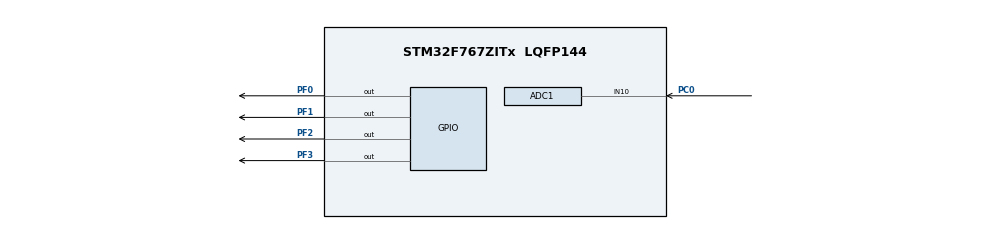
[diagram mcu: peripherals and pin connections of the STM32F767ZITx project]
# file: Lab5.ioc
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ADC1.Channel-0\#ChannelRegularConversion=ADC_CHANNEL_10
ADC1.ContinuousConvMode=ENABLE
ADC1.EOCSelection=ADC_EOC_SEQ_CONV
ADC1.NbrOfConversionFlag=1
ADC1.Rank-0\#ChannelRegularConversion=1
ADC1.SamplingTime-0\#ChannelRegularConversion=ADC_SAMPLETIME_3CYCLES
ADC1.master=1
CORTEX_M7.default_mode_Activation=1
Mcu.Family=STM32F7
Mcu.Name=STM32F767ZITx
Mcu.Package=LQFP144
NVIC.PriorityGroup=NVIC_PRIORITYGROUP_4
PC0.Signal=ADCx_IN10
PF0.Signal=GPIO_Output
PF1.Signal=GPIO_Output
PF2.Signal=GPIO_Output
PF3.Signal=GPIO_Output
ProjectManager.HeapSize=0x200
ProjectManager.StackSize=0x400
ProjectManager.TargetToolchain=STM32CubeIDE
RCC.AHBFreq_Value=216000000
RCC.APB1CLKDivider=RCC_HCLK_DIV4
RCC.APB1Freq_Value=54000000
RCC.APB1TimFreq_Value=108000000
RCC.APB2CLKDivider=RCC_HCLK_DIV2
RCC.APB2Freq_Value=108000000
RCC.APB2TimFreq_Value=216000000
RCC.CortexFreq_Value=216000000
RCC.HCLKFreq_Value=216000000
RCC.HSE_VALUE=25000000
RCC.HSI_VALUE=16000000
RCC.LSE_VALUE=32768
RCC.PLLM=8
RCC.PLLN=216
RCC.SYSCLKFreq_VALUE=216000000
RCC.SYSCLKSource=RCC_SYSCLKSOURCE_PLLCLK
RCC.USBFreq_Value=216000000
RCC.VCOOutputFreq_Value=432000000
SH.ADCx_IN10.0=ADC1_IN10,IN10
board=custom

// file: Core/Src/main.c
/* USER CODE BEGIN Header */
/**
  ******************************************************************************
  * @file           : main.c
  * @brief          : Main program body
  ******************************************************************************
  * @attention
  *
  * Copyright (c) 2026 STMicroelectronics.
  * All rights reserved.
  *
  * This software is licensed under terms that can be found in the LICENSE file
  * in the root directory of this software component.
  * If no LICENSE file comes with this software, it is provided AS-IS.
  *
  ******************************************************************************
  */
/* USER CODE END Header */
#include "main.h"

ADC_HandleTypeDef hadc1;

/* USER CODE BEGIN PV */
volatile uint32_t adc_val = 0;
volatile uint32_t avg8 = 0;
volatile uint32_t avg16 = 0;
float vout = 0;
float vout8 = 0;
float vout16 = 0;
/* USER CODE END PV */

void SystemClock_Config(void);
static void MPU_Config(void);
static void MX_GPIO_Init(void);
static void MX_ADC1_Init(void);

/* USER CODE BEGIN 0 */
int average_8(int x){
	static int sample[8];
	static int i = 0;
	static int total = 0;
	total += x - sample[i];
	sample[i] = x;
	i = (i==7?0 : i+1);
	return total>>3;
}

int average_16(int x){
	static int sample[16];
	static int i = 0;
	static int total = 0;
	total += x - sample[i];
	sample[i] = x;
	i = (i==15?0 : i+1);
	return total>>4;
}
/* USER CODE END 0 */

int main(void)
{

  /* MPU Configuration--------------------------------------------------------*/
  MPU_Config();

  /* MCU Configuration--------------------------------------------------------*/

  /* Reset of all peripherals, Initializes the Flash interface and the Systick. */
  HAL_Init();

  /* Configure the system clock */
  SystemClock_Config();

  /* Initialize all configured peripherals */
  MX_GPIO_Init();
  MX_ADC1_Init();
  /* USER CODE BEGIN 2 */
  HAL_ADC_Start(&hadc1);
  /* USER CODE END 2 */

  /* Infinite loop */
  while (1)
  {

    /* USER CODE BEGIN 3 */
//	  while(HAL_ADC_PollForConversion(&hadc1,100)!= HAL_OK){
//		  adc_val = HAL_ADC_GetValue(&hadc1);
//	  }
	 HAL_ADC_PollForConversion(&hadc1, HAL_MAX_DELAY);
	 adc_val = HAL_ADC_GetValue(&hadc1);
	 vout = adc_val * 3.3f / 4095.0f;
	 avg8 = average_8(adc_val);
	 vout8 = avg8 * 3.3f / 4095.0f;
	 avg16 = average_16(adc_val);
	 vout16 = avg16 * 3.3f / 4095.0f;
  }
  /* USER CODE END 3 */
}

void SystemClock_Config(void)
{
  RCC_OscInitTypeDef RCC_OscInitStruct = {0};
  RCC_ClkInitTypeDef RCC_ClkInitStruct = {0};

  /** Configure the main internal regulator output voltage
  */
  __HAL_RCC_PWR_CLK_ENABLE();
  __HAL_PWR_VOLTAGESCALING_CONFIG(PWR_REGULATOR_VOLTAGE_SCALE3);

  /** Initializes the RCC Oscillators according to the specified parameters
  * in the RCC_OscInitTypeDef structure.
  */
  RCC_OscInitStruct.OscillatorType = RCC_OSCILLATORTYPE_HSI;
  RCC_OscInitStruct.HSIState = RCC_HSI_ON;
  RCC_OscInitStruct.HSICalibrationValue = RCC_HSICALIBRATION_DEFAULT;
  RCC_OscInitStruct.PLL.PLLState = RCC_PLL_NONE;
  if (HAL_RCC_OscConfig(&RCC_OscInitStruct) != HAL_OK)
  {
    Error_Handler();
  }

  /** Initializes the CPU, AHB and APB buses clocks
  */
  RCC_ClkInitStruct.ClockType = RCC_CLOCKTYPE_HCLK|RCC_CLOCKTYPE_SYSCLK
                              |RCC_CLOCKTYPE_PCLK1|RCC_CLOCKTYPE_PCLK2;
  RCC_ClkInitStruct.SYSCLKSource = RCC_SYSCLKSOURCE_HSI;
  RCC_ClkInitStruct.AHBCLKDivider = RCC_SYSCLK_DIV1;
  RCC_ClkInitStruct.APB1CLKDivider = RCC_HCLK_DIV1;
  RCC_ClkInitStruct.APB2CLKDivider = RCC_HCLK_DIV1;

  if (HAL_RCC_ClockConfig(&RCC_ClkInitStruct, FLASH_LATENCY_0) != HAL_OK)
  {
    Error_Handler();
  }
}

static void MX_ADC1_Init(void)
{

  ADC_ChannelConfTypeDef sConfig = {0};

  /** Configure the global features of the ADC (Clock, Resolution, Data Alignment and number of conversion)
  */
  hadc1.Instance = ADC1;
  hadc1.Init.ClockPrescaler = ADC_CLOCK_SYNC_PCLK_DIV2;
  hadc1.Init.Resolution = ADC_RESOLUTION_12B;
  hadc1.Init.ScanConvMode = ADC_SCAN_DISABLE;
  hadc1.Init.ContinuousConvMode = ENABLE;
  hadc1.Init.DiscontinuousConvMode = DISABLE;
  hadc1.Init.ExternalTrigConvEdge = ADC_EXTERNALTRIGCONVEDGE_NONE;
  hadc1.Init.ExternalTrigConv = ADC_SOFTWARE_START;
  hadc1.Init.DataAlign = ADC_DATAALIGN_RIGHT;
  hadc1.Init.NbrOfConversion = 1;
  hadc1.Init.DMAContinuousRequests = DISABLE;
  hadc1.Init.EOCSelection = ADC_EOC_SEQ_CONV;
  if (HAL_ADC_Init(&hadc1) != HAL_OK)
  {
    Error_Handler();
  }

  /** Configure for the selected ADC regular channel its corresponding rank in the sequencer and its sample time.
  */
  sConfig.Channel = ADC_CHANNEL_10;
  sConfig.Rank = ADC_REGULAR_RANK_1;
  sConfig.SamplingTime = ADC_SAMPLETIME_3CYCLES;
  if (HAL_ADC_ConfigChannel(&hadc1, &sConfig) != HAL_OK)
  {
    Error_Handler();
  }

}

static void MX_GPIO_Init(void)
{
  GPIO_InitTypeDef GPIO_InitStruct = {0};

  /* GPIO Ports Clock Enable */
  __HAL_RCC_GPIOF_CLK_ENABLE();
  __HAL_RCC_GPIOC_CLK_ENABLE();

  /*Configure GPIO pin Output Level */
  HAL_GPIO_WritePin(GPIOF, GPIO_PIN_0|GPIO_PIN_1|GPIO_PIN_2|GPIO_PIN_3, GPIO_PIN_RESET);

  /*Configure GPIO pins : PF0 PF1 PF2 PF3 */
  GPIO_InitStruct.Pin = GPIO_PIN_0|GPIO_PIN_1|GPIO_PIN_2|GPIO_PIN_3;
  GPIO_InitStruct.Mode = GPIO_MODE_OUTPUT_PP;
  GPIO_InitStruct.Pull = GPIO_NOPULL;
  GPIO_InitStruct.Speed = GPIO_SPEED_FREQ_LOW;
  HAL_GPIO_Init(GPIOF, &GPIO_InitStruct);

}

 /* MPU Configuration */

void MPU_Config(void)
{
  MPU_Region_InitTypeDef MPU_InitStruct = {0};

  /* Disables the MPU */
  HAL_MPU_Disable();

  /** Initializes and configures the Region and the memory to be protected
  */
  MPU_InitStruct.Enable = MPU_REGION_ENABLE;
  MPU_InitStruct.Number = MPU_REGION_NUMBER0;
  MPU_InitStruct.BaseAddress = 0x0;
  MPU_InitStruct.Size = MPU_REGION_SIZE_4GB;
  MPU_InitStruct.SubRegionDisable = 0x87;
  MPU_InitStruct.TypeExtField = MPU_TEX_LEVEL0;
  MPU_InitStruct.AccessPermission = MPU_REGION_NO_ACCESS;
  MPU_InitStruct.DisableExec = MPU_INSTRUCTION_ACCESS_DISABLE;
  MPU_InitStruct.IsShareable = MPU_ACCESS_SHAREABLE;
  MPU_InitStruct.IsCacheable = MPU_ACCESS_NOT_CACHEABLE;
  MPU_InitStruct.IsBufferable = MPU_ACCESS_NOT_BUFFERABLE;

  HAL_MPU_ConfigRegion(&MPU_InitStruct);
  /* Enables the MPU */
  HAL_MPU_Enable(MPU_PRIVILEGED_DEFAULT);

}

void Error_Handler(void)
{
  __disable_irq();
  while (1)
  {
  }
}
